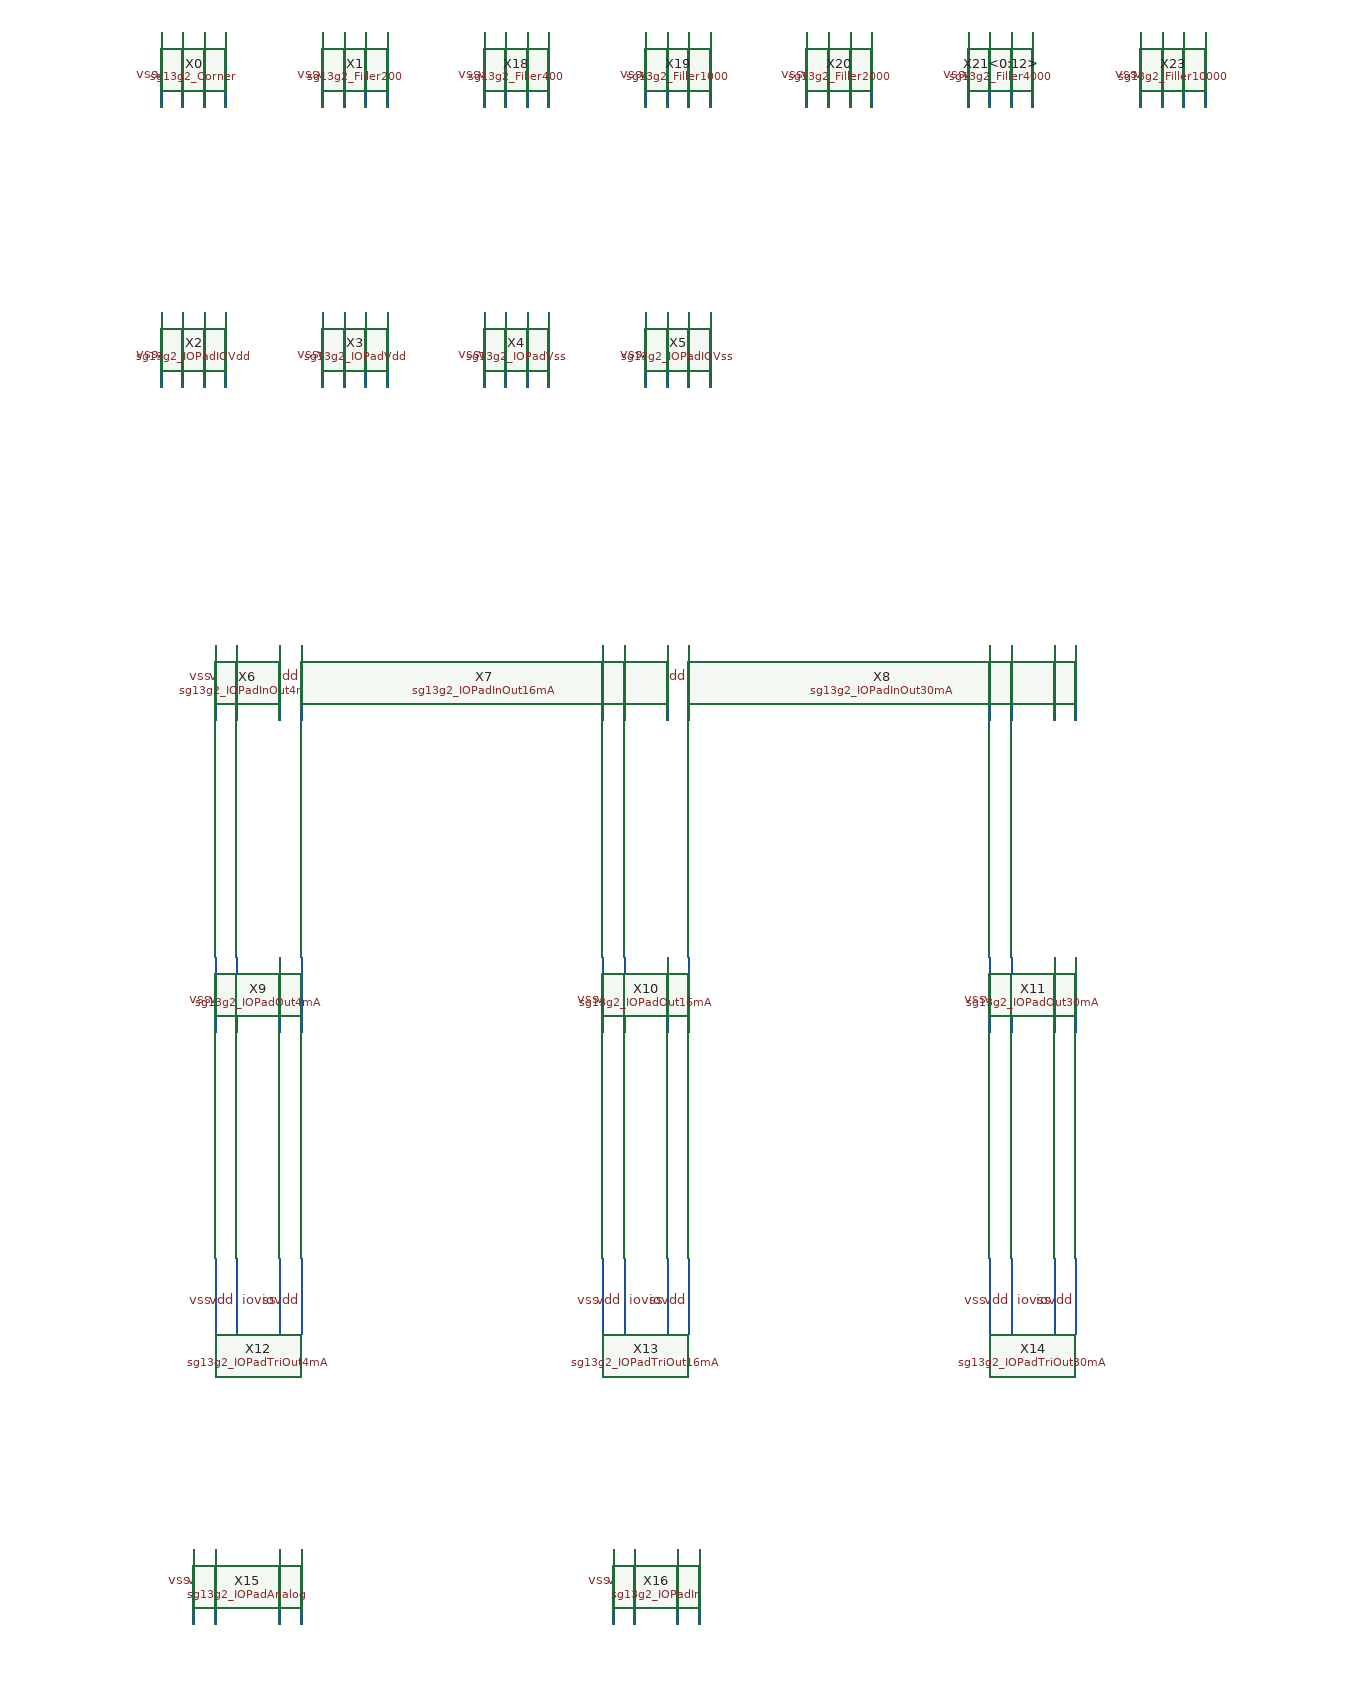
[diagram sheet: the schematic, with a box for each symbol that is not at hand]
v {xschem version=3.4.7 file_version=1.2}
G {}
K {}
V {}
S {}
E {}
N 120 -210 120 -280 {lab=vss}
N 140 -210 140 -280 {lab=vdd}
N 160 -210 160 -280 {lab=iovss}
N 180 -210 180 -280 {lab=iovdd}
N 590 -210 590 -280 {lab=vdd}
N 610 -210 610 -280 {lab=iovss}
N 630 -210 630 -280 {lab=iovdd}
N 570 -210 570 -280 {lab=vss}
N 270 -210 270 -280 {lab=vss}
N 330 -210 330 -280 {lab=iovdd}
N 310 -210 310 -280 {lab=iovss}
N 290 -210 290 -280 {lab=vdd}
N 440 -210 440 -280 {lab=vdd}
N 460 -210 460 -280 {lab=iovss}
N 480 -210 480 -280 {lab=iovdd}
N 420 -210 420 -280 {lab=vss}
N 760 -470 760 -540 {lab=iovss}
N 910 -470 910 -540 {lab=iovss}
N 720 -470 720 -540 {lab=vss}
N 740 -470 740 -540 {lab=vdd}
N 170 100 170 30 {lab=vss}
N 250 100 250 30 {lab=iovdd}
N 230 100 230 30 {lab=iovss}
N 190 100 190 30 {lab=vdd}
N 890 100 890 30 {lab=vss}
N 970 100 970 30 {lab=iovdd}
N 950 100 950 30 {lab=iovss}
N 910 100 910 30 {lab=vdd}
N 190 390 190 320 {lab=vdd}
N 230 390 230 320 {lab=iovss}
N 250 390 250 320 {lab=iovdd}
N 170 390 170 320 {lab=vss}
N 890 390 890 320 {lab=vss}
N 970 390 970 320 {lab=iovdd}
N 950 390 950 320 {lab=iovss}
N 910 390 910 320 {lab=vdd}
N 540 940 540 870 {lab=vss}
N 620 940 620 870 {lab=iovdd}
N 600 940 600 870 {lab=iovss}
N 560 940 560 870 {lab=vdd}
N 530 100 530 30 {lab=vss}
N 550 100 550 30 {lab=vdd}
N 590 100 590 30 {lab=iovss}
N 610 100 610 30 {lab=iovdd}
N 530 390 530 320 {lab=vss}
N 550 390 550 320 {lab=vdd}
N 590 390 590 320 {lab=iovss}
N 610 390 610 320 {lab=iovdd}
N 250 670 250 600 {lab=iovdd}
N 230 670 230 600 {lab=iovss}
N 190 670 190 600 {lab=vdd}
N 170 670 170 600 {lab=vss}
N 530 670 530 600 {lab=vss}
N 550 670 550 600 {lab=vdd}
N 590 670 590 600 {lab=iovss}
N 610 670 610 600 {lab=iovdd}
N 970 670 970 600 {lab=iovdd}
N 950 670 950 600 {lab=iovss}
N 910 670 910 600 {lab=vdd}
N 890 670 890 600 {lab=vss}
N 120 -470 120 -540 {lab=vss}
N 140 -470 140 -540 {lab=vdd}
N 160 -470 160 -540 {lab=iovss}
N 180 -470 180 -540 {lab=iovdd}
N 870 -470 870 -540 {lab=vss}
N 890 -470 890 -540 {lab=vdd}
N 930 -470 930 -540 {lab=iovdd}
N 1030 -470 1030 -540 {lab=vss}
N 780 -470 780 -540 {lab=iovdd}
N 630 -470 630 -540 {lab=iovdd}
N 610 -470 610 -540 {lab=iovss}
N 590 -470 590 -540 {lab=vdd}
N 270 -470 270 -540 {lab=vss}
N 290 -470 290 -540 {lab=vdd}
N 310 -470 310 -540 {lab=iovss}
N 330 -470 330 -540 {lab=iovdd}
N 420 -470 420 -540 {lab=vss}
N 440 -470 440 -540 {lab=vdd}
N 460 -470 460 -540 {lab=iovss}
N 480 -470 480 -540 {lab=iovdd}
N 570 -470 570 -540 {lab=vss}
N 150 940 150 870 {lab=vss}
N 170 940 170 870 {lab=vdd}
N 230 940 230 870 {lab=iovss}
N 250 940 250 870 {lab=iovdd}
N 1050 -470 1050 -540 {lab=vdd}
N 1070 -470 1070 -540 {lab=iovss}
N 1090 -470 1090 -540 {lab=iovdd}
C {lab_wire.sym} 120 -240 0 0 {name=l1 sig_type=std_logic lab=vss}
C {lab_wire.sym} 140 -240 0 0 {name=l2 sig_type=std_logic lab=vdd}
C {lab_wire.sym} 160 -240 0 0 {name=l3 sig_type=std_logic lab=iovss}
C {lab_wire.sym} 180 -240 0 0 {name=l4 sig_type=std_logic lab=iovdd}
C {lab_wire.sym} 590 -240 0 0 {name=l5 sig_type=std_logic lab=vdd}
C {lab_wire.sym} 610 -240 0 0 {name=l6 sig_type=std_logic lab=iovss}
C {lab_wire.sym} 630 -240 0 0 {name=l7 sig_type=std_logic lab=iovdd}
C {lab_wire.sym} 570 -240 0 0 {name=l8 sig_type=std_logic lab=vss}
C {lab_wire.sym} 270 -240 0 0 {name=l9 sig_type=std_logic lab=vss}
C {lab_wire.sym} 330 -240 0 0 {name=l10 sig_type=std_logic lab=iovdd}
C {lab_wire.sym} 310 -240 0 0 {name=l11 sig_type=std_logic lab=iovss}
C {lab_wire.sym} 290 -240 0 0 {name=l12 sig_type=std_logic lab=vdd}
C {lab_wire.sym} 440 -240 0 0 {name=l13 sig_type=std_logic lab=vdd}
C {lab_wire.sym} 460 -240 0 0 {name=l14 sig_type=std_logic lab=iovss}
C {lab_wire.sym} 480 -240 0 0 {name=l15 sig_type=std_logic lab=iovdd}
C {lab_wire.sym} 420 -240 0 0 {name=l16 sig_type=std_logic lab=vss}
C {lab_wire.sym} 760 -500 0 0 {name=l17 sig_type=std_logic lab=iovss}
C {lab_wire.sym} 910 -500 0 0 {name=l18 sig_type=std_logic lab=iovss}
C {lab_wire.sym} 720 -500 0 0 {name=l19 sig_type=std_logic lab=vss}
C {lab_wire.sym} 740 -500 0 0 {name=l20 sig_type=std_logic lab=vdd}
C {lab_wire.sym} 170 60 0 0 {name=l21 sig_type=std_logic lab=vss}
C {lab_wire.sym} 250 60 0 0 {name=l22 sig_type=std_logic lab=iovdd}
C {lab_wire.sym} 230 60 0 0 {name=l23 sig_type=std_logic lab=iovss}
C {lab_wire.sym} 190 60 0 0 {name=l24 sig_type=std_logic lab=vdd}
C {lab_wire.sym} 890 60 0 0 {name=l25 sig_type=std_logic lab=vss}
C {lab_wire.sym} 970 60 0 0 {name=l26 sig_type=std_logic lab=iovdd}
C {lab_wire.sym} 950 60 0 0 {name=l27 sig_type=std_logic lab=iovss}
C {lab_wire.sym} 910 60 0 0 {name=l28 sig_type=std_logic lab=vdd}
C {lab_wire.sym} 190 360 0 0 {name=l29 sig_type=std_logic lab=vdd}
C {lab_wire.sym} 230 360 0 0 {name=l30 sig_type=std_logic lab=iovss}
C {lab_wire.sym} 250 360 0 0 {name=l31 sig_type=std_logic lab=iovdd}
C {lab_wire.sym} 170 360 0 0 {name=l32 sig_type=std_logic lab=vss}
C {lab_wire.sym} 890 360 0 0 {name=l33 sig_type=std_logic lab=vss}
C {lab_wire.sym} 970 360 0 0 {name=l34 sig_type=std_logic lab=iovdd}
C {lab_wire.sym} 950 360 0 0 {name=l35 sig_type=std_logic lab=iovss}
C {lab_wire.sym} 910 360 0 0 {name=l36 sig_type=std_logic lab=vdd}
C {lab_wire.sym} 540 900 0 0 {name=l37 sig_type=std_logic lab=vss}
C {lab_wire.sym} 620 900 0 0 {name=l38 sig_type=std_logic lab=iovdd}
C {lab_wire.sym} 600 900 0 0 {name=l39 sig_type=std_logic lab=iovss}
C {lab_wire.sym} 560 900 0 0 {name=l40 sig_type=std_logic lab=vdd}
C {lab_wire.sym} 530 60 0 0 {name=l41 sig_type=std_logic lab=vss}
C {lab_wire.sym} 550 60 0 0 {name=l42 sig_type=std_logic lab=vdd}
C {lab_wire.sym} 590 60 0 0 {name=l43 sig_type=std_logic lab=iovss}
C {lab_wire.sym} 610 60 0 0 {name=l44 sig_type=std_logic lab=iovdd}
C {lab_wire.sym} 530 360 0 0 {name=l45 sig_type=std_logic lab=vss}
C {lab_wire.sym} 550 360 0 0 {name=l46 sig_type=std_logic lab=vdd}
C {lab_wire.sym} 590 360 0 0 {name=l47 sig_type=std_logic lab=iovss}
C {lab_wire.sym} 610 360 0 0 {name=l48 sig_type=std_logic lab=iovdd}
C {lab_wire.sym} 250 640 0 0 {name=l49 sig_type=std_logic lab=iovdd}
C {lab_wire.sym} 230 640 0 0 {name=l50 sig_type=std_logic lab=iovss}
C {lab_wire.sym} 190 640 0 0 {name=l51 sig_type=std_logic lab=vdd}
C {lab_wire.sym} 170 640 0 0 {name=l52 sig_type=std_logic lab=vss}
C {lab_wire.sym} 530 640 0 0 {name=l53 sig_type=std_logic lab=vss}
C {lab_wire.sym} 550 640 0 0 {name=l54 sig_type=std_logic lab=vdd}
C {lab_wire.sym} 590 640 0 0 {name=l55 sig_type=std_logic lab=iovss}
C {lab_wire.sym} 610 640 0 0 {name=l56 sig_type=std_logic lab=iovdd}
C {lab_wire.sym} 970 640 0 0 {name=l57 sig_type=std_logic lab=iovdd}
C {lab_wire.sym} 950 640 0 0 {name=l58 sig_type=std_logic lab=iovss}
C {lab_wire.sym} 910 640 0 0 {name=l59 sig_type=std_logic lab=vdd}
C {lab_wire.sym} 890 640 0 0 {name=l60 sig_type=std_logic lab=vss}
C {lab_wire.sym} 120 -500 0 0 {name=l61 sig_type=std_logic lab=vss}
C {lab_wire.sym} 140 -500 0 0 {name=l62 sig_type=std_logic lab=vdd}
C {lab_wire.sym} 160 -500 0 0 {name=l63 sig_type=std_logic lab=iovss}
C {lab_wire.sym} 180 -500 0 0 {name=l64 sig_type=std_logic lab=iovdd}
C {lab_wire.sym} 870 -500 0 0 {name=l65 sig_type=std_logic lab=vss}
C {lab_wire.sym} 890 -500 0 0 {name=l66 sig_type=std_logic lab=vdd}
C {lab_wire.sym} 930 -500 0 0 {name=l67 sig_type=std_logic lab=iovdd}
C {lab_wire.sym} 1030 -500 0 0 {name=l68 sig_type=std_logic lab=vss}
C {lab_wire.sym} 780 -500 0 0 {name=l69 sig_type=std_logic lab=iovdd}
C {lab_wire.sym} 630 -500 0 0 {name=l70 sig_type=std_logic lab=iovdd}
C {lab_wire.sym} 610 -500 0 0 {name=l71 sig_type=std_logic lab=iovss}
C {lab_wire.sym} 590 -500 0 0 {name=l72 sig_type=std_logic lab=vdd}
C {lab_wire.sym} 270 -500 0 0 {name=l73 sig_type=std_logic lab=vss}
C {lab_wire.sym} 290 -500 0 0 {name=l74 sig_type=std_logic lab=vdd}
C {lab_wire.sym} 310 -500 0 0 {name=l75 sig_type=std_logic lab=iovss}
C {lab_wire.sym} 330 -500 0 0 {name=l76 sig_type=std_logic lab=iovdd}
C {lab_wire.sym} 420 -500 0 0 {name=l77 sig_type=std_logic lab=vss}
C {lab_wire.sym} 440 -500 0 0 {name=l78 sig_type=std_logic lab=vdd}
C {lab_wire.sym} 460 -500 0 0 {name=l79 sig_type=std_logic lab=iovss}
C {lab_wire.sym} 480 -500 0 0 {name=l80 sig_type=std_logic lab=iovdd}
C {lab_wire.sym} 570 -500 0 0 {name=l81 sig_type=std_logic lab=vss}
C {lab_wire.sym} 150 900 0 0 {name=l82 sig_type=std_logic lab=vss}
C {lab_wire.sym} 170 900 0 0 {name=l83 sig_type=std_logic lab=vdd}
C {lab_wire.sym} 230 900 0 0 {name=l84 sig_type=std_logic lab=iovss}
C {lab_wire.sym} 250 900 0 0 {name=l85 sig_type=std_logic lab=iovdd}
C {lab_wire.sym} 1050 -500 0 0 {name=l86 sig_type=std_logic lab=vdd}
C {lab_wire.sym} 1070 -500 0 0 {name=l87 sig_type=std_logic lab=iovss}
C {lab_wire.sym} 1090 -500 0 0 {name=l88 sig_type=std_logic lab=iovdd}
C {sg13g2_Corner.sym} 120 -470 0 0 {name=X0}
C {sg13g2_Filler200.sym} 270 -470 0 0 {name=X1}
C {sg13g2_IOPadOut16mA.sym} 450 480 0 0 {name=X10}
C {sg13g2_IOPadOut30mA.sym} 810 480 0 0 {name=X11}
C {sg13g2_IOPadTriOut4mA.sym} 90 760 0 0 {name=X12}
C {sg13g2_IOPadTriOut16mA.sym} 450 760 0 0 {name=X13}
C {sg13g2_IOPadTriOut30mA.sym} 810 760 0 0 {name=X14}
C {sg13g2_IOPadAnalog.sym} 150 940 0 0 {name=X15}
C {sg13g2_IOPadIn.sym} 540 940 0 0 {name=X16}
C {sg13g2_Filler400.sym} 420 -470 0 0 {name=X18}
C {sg13g2_Filler1000.sym} 570 -470 0 0 {name=X19}
C {sg13g2_IOPadIOVdd.sym} 120 -210 0 0 {name=X2}
C {sg13g2_Filler2000.sym} 720 -470 0 0 {name=X20}
C {sg13g2_Filler4000.sym} 870 -470 0 0 {name=X21<0:12>}
C {sg13g2_Filler10000.sym} 1030 -470 0 0 {name=X23}
C {sg13g2_IOPadVdd.sym} 270 -210 0 0 {name=X3}
C {sg13g2_IOPadVss.sym} 420 -210 0 0 {name=X4}
C {sg13g2_IOPadIOVss.sym} 570 -210 0 0 {name=X5}
C {sg13g2_IOPadInOut4mA.sym} 60 190 0 0 {name=X6}
C {sg13g2_IOPadInOut16mA.sym} 420 190 0 0 {name=X7}
C {sg13g2_IOPadInOut30mA.sym} 780 190 0 0 {name=X8}
C {sg13g2_IOPadOut4mA.sym} 90 480 0 0 {name=X9}
C {devices/title-2.sym} -1140 1420 0 0 {name=l1 author="IHP PDK AUTHORS"}
